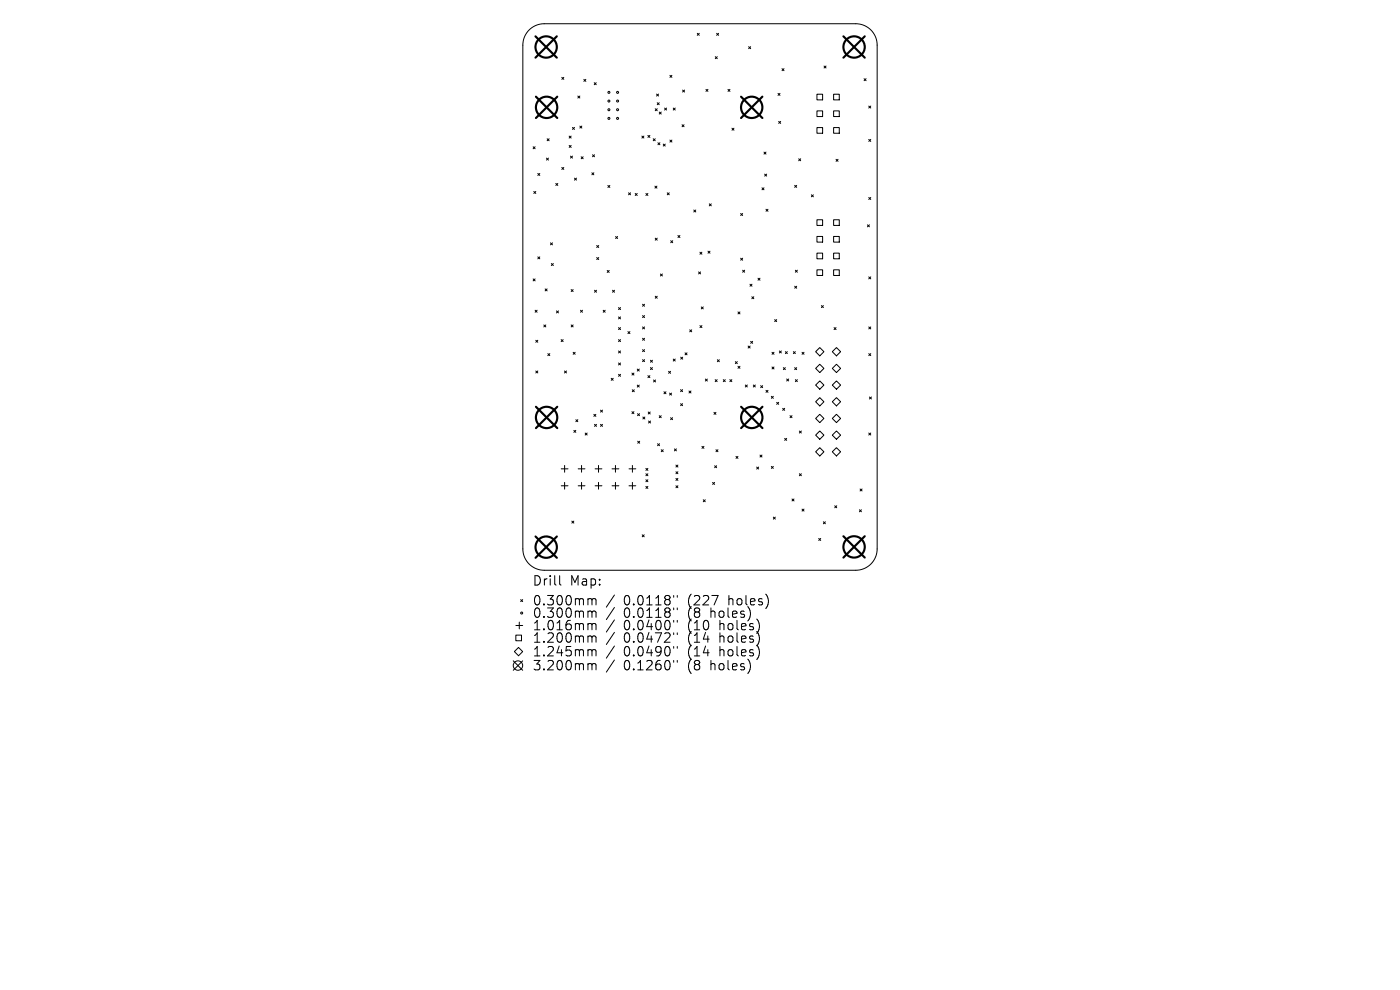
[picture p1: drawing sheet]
<svg xmlns="http://www.w3.org/2000/svg" width="297mm" height="210mm" viewBox="0 0 297 210" stroke-linecap="round" stroke-linejoin="round" font-family="sans-serif">
<defs><g id="words">
<g font-size="2.8">
<text x="112.9" y="124.5">Drill</text>
<text x="120.9" y="124.5">Map:</text>
<text x="112.9" y="128.7">0.300mm</text>
<text x="112.9" y="131.3">0.300mm</text>
<text x="132.3" y="128.7">0.0118&quot;</text>
<text x="132.3" y="131.3">0.0118&quot;</text>
<text x="146.1" y="128.7">(227</text>
<text x="146.1" y="131.3">(8</text>
<text x="151" y="131.3">holes)</text>
<text x="154.8" y="128.7">holes)</text>
<text x="112.9" y="134">1.016mm</text>
<text x="112.9" y="136.6">1.200mm</text>
<text x="132.3" y="134">0.0400&quot;</text>
<text x="132.3" y="136.6">0.0472&quot;</text>
<text x="146.1" y="134">(10</text>
<text x="146.1" y="136.6">(14</text>
<text x="152.9" y="134">holes)</text>
<text x="152.9" y="136.6">holes)</text>
<text x="112.9" y="139.5">1.245mm</text>
<text x="112.9" y="142.5">3.200mm</text>
<text x="132.3" y="139.5">0.0490&quot;</text>
<text x="132.3" y="142.5">0.1260&quot;</text>
<text x="146.1" y="139.5">(14</text>
<text x="146.1" y="142.5">(8</text>
<text x="151" y="142.5">holes)</text>
<text x="152.9" y="139.5">holes)</text>
</g>
</g></defs>
<g fill="none" stroke="#000" stroke-width=".21">
<path d="M112.2 6.4a4.5 4.5 0 0 1 3.2-1.4h66.2a4.5 4.5 0 0 1 4.5 4.6v106.8a4.5 4.5 0 0 1-4.5 4.6h-66.2a4.5 4.5 0 0 1-4.5-4.6v-106.8a4.5 4.5 0 0 1 1.3-3.2zM119.2 16.4l.4 .4M119.6 16.4l-.4 .4M123.9 16.8l.4 .5M124.3 16.8l-.4 .5M126.1 17.5l.4 .5M126.5 17.5l-.4 .5M139.3 19.9l.4 .5M139.7 19.9l-.4 .5M142.1 16l.4 .4M142.5 16l-.4 .4M144.8 19.1l.4 .4"/>
<path d="M145.2 19.1l-.4 .4M147.9 7.1l.4 .4M148.3 7.1l-.4 .4M149.8 19l.4 .4M150.2 19l-.4 .4M151.7 12l.5 .4M152 7.1l.5 .4M152.2 12l-.5 .4M152.5 7.1l-.5 .4M154.4 19l.5 .4M154.9 19l-.5 .4M158.8 9.9l.4 .4"/>
<path d="M159.2 9.9l-.4 .4M165.1 19.8l.4 .4M165.5 19.8l-.4 .4M165.9 14.6l.4 .4M166.3 14.6l-.4 .4M173.3 20h1.2v1.2h-1.2zM174.8 14l.4 .4M175.2 14l-.4 .4M176.8 20h1.2v1.2h-1.2zM183.3 16.7l.4 .4M183.7 16.7l-.4 .4M113.1 31.1l.4 .5"/>
<path d="M113.5 31.1l-.4 .5M114.1 36.8l.4 .4M114.5 36.8l-.4 .4M115.9 33.5l.5 .5M116.1 29.4l.4 .5M116.4 33.5l-.5 .5M116.5 29.4l-.4 .5M117.9 38.9l.4 .4M118.3 38.9l-.4 .4M119.2 35.5l.4 .4M119.6 35.5l-.4 .4M120.7 28.9l.5 .4"/>
<path d="M120.7 30.8l.5 .5M121 33.1l.5 .4M121.2 28.9l-.5 .4M121.2 30.8l-.5 .5M121.5 33.1l-.5 .4M121.5 27l.4 .5M121.9 27l-.4 .5M121.9 37.8l.4 .4M122.3 37.8l-.4 .4M122.6 20.4l.4 .4M123 20.4l-.4 .4M123 26.7l.4 .5"/>
<path d="M123.3 33.3l.4 .4M123.4 26.7l-.4 .5M123.7 33.3l-.4 .4M125.6 36.7l.4 .4M125.7 32.8l.4 .5M126 36.7l-.4 .4M126.1 32.8l-.4 .5M129 39.3l.4 .5M129.4 39.3l-.4 .5M136.2 28.9l.4 .4M136.6 28.9l-.4 .4M137.4 28.7l.5 .5"/>
<path d="M137.9 28.7l-.5 .5M138.6 29.4l.4 .5M138.9 39.5l.5 .4M139 29.4l-.4 .5M139 23.1l.4 .4M139.4 39.5l-.5 .4M139.4 23.1l-.4 .4M139.4 21.8l.5 .4M139.6 30.3l.4 .4M139.9 21.8l-.5 .4M139.9 23.8l.4 .4M140 30.3l-.4 .4"/>
<path d="M140.3 23.8l-.4 .4M140.7 30.6l.4 .4M141 22.9l.4 .4M141.1 30.6l-.4 .4M141.4 22.9l-.4 .4M142.1 29.7l.4 .4M142.5 29.7l-.4 .4M142.8 22.9l.5 .4M143.3 22.9l-.5 .4M144.7 26.5l.4 .4M145.1 26.5l-.4 .4M155.3 27.2l.4 .4"/>
<path d="M155.7 27.2l-.4 .4M161.7 39.8l.4 .5M162.1 39.8l-.4 .5M162.1 32.3l.4 .4M162.2 36.9l.4 .5M162.5 32.3l-.4 .4M162.6 36.9l-.4 .5M165.2 25.8l.4 .4M165.6 25.8l-.4 .4M168.6 39.3l.4 .4M169 39.3l-.4 .4M169.4 33.7l.5 .4"/>
<path d="M169.9 33.7l-.5 .4M173.3 23.5h1.2v1.2h-1.2zM173.3 27.1h1.2v1.2h-1.2zM176.8 23.5h1.2v1.2h-1.2zM176.8 27.1h1.2v1.2h-1.2zM177.4 33.8l.4 .4M177.8 33.8l-.4 .4M184.3 22.5l.4 .4M184.3 29.6l.4 .4M184.7 22.5l-.4 .4M184.7 29.6l-.4 .4M113.1 59.2l.4 .4"/>
<path d="M113.2 40.6l.5 .4M113.5 59.2l-.4 .4M113.7 40.6l-.5 .4M114.1 54.5l.4 .4M114.5 54.5l-.4 .4M116.8 51.5l.4 .4M117 55.9l.4 .4M117.2 51.5l-.4 .4M117.4 55.9l-.4 .4M126.6 52.1l.4 .4M126.6 54.6l.4 .5M127 52.1l-.4 .4"/>
<path d="M127 54.6l-.4 .5M128.8 57.4l.4 .4M129.2 57.4l-.4 .4M130.6 50.2l.4 .4M131 50.2l-.4 .4M133.3 40.9l.5 .4M133.8 40.9l-.5 .4M134.8 41l.4 .5M135.2 41l-.4 .5M137 41l.4 .5M137.4 41l-.4 .5M139 50.5l.4 .5"/>
<path d="M139.4 50.5l-.4 .5M140.1 58.1l.4 .4M140.5 58.1l-.4 .4M141.6 40.9l.4 .4M142 40.9l-.4 .4M142.3 51.1l.4 .4M142.7 51.1l-.4 .4M143.8 50l.4 .4M144.2 50l-.4 .4M147.2 44.5l.4 .5M147.6 44.5l-.4 .5M148.2 57.7l.4 .4"/>
<path d="M148.5 53.5l.4 .4M148.6 57.7l-.4 .4M148.9 53.5l-.4 .4M150.2 53.3l.4 .4M150.5 43.2l.4 .5M150.6 53.3l-.4 .4M150.9 43.2l-.4 .5M157.1 45.3l.4 .4M157.1 54.8l.4 .4M157.5 45.3l-.4 .4M157.5 54.8l-.4 .4M157.5 57.3l.5 .4"/>
<path d="M158 57.3l-.5 .4M160.8 59l.4 .4M161.2 59l-.4 .4M162.5 44.4l.4 .4M162.9 44.4l-.4 .4M168.7 57.3l.5 .4M169.2 57.3l-.5 .4M172.1 41.3l.5 .4M172.6 41.3l-.5 .4M173.3 46.6h1.2v1.2h-1.2zM173.3 50.2h1.2v1.2h-1.2zM173.3 53.7h1.2v1.2h-1.2z"/>
<path d="M173.3 57.2h1.2v1.2h-1.2zM176.8 46.6h1.2v1.2h-1.2zM176.8 50.2h1.2v1.2h-1.2zM176.8 53.7h1.2v1.2h-1.2zM176.8 57.2h1.2v1.2h-1.2zM184 47.7l.4 .4M184.3 41.9l.4 .4M184.3 58.7l.4 .5M184.4 47.7l-.4 .4M184.7 41.9l-.4 .4M184.7 58.7l-.4 .5M113.5 65.8l.4 .4"/>
<path d="M113.7 72.2l.4 .4M113.7 78.7l.4 .4M113.9 65.8l-.4 .4M114.1 72.2l-.4 .4M114.1 78.7l-.4 .4M115.4 68.9l.4 .5M115.6 61.3l.5 .4M115.8 68.9l-.4 .5M116.1 61.3l-.5 .4M116.2 75l.4 .4M116.6 75l-.4 .4M118.1 66l.4 .4"/>
<path d="M118.5 66l-.4 .4M119 72l.5 .5M119.5 72l-.5 .5M119.8 78.7l.4 .4M120.2 78.7l-.4 .4M121.2 61.4l.4 .4M121.2 68.9l.4 .5M121.6 61.4l-.4 .4M121.6 68.9l-.4 .5M121.6 74.7l.4 .5M122 74.7l-.4 .5M123.2 65.8l.4 .4"/>
<path d="M123.6 65.8l-.4 .4M126.1 61.6l.4 .4M126.5 61.6l-.4 .4M128 65.8l.4 .4M128.4 65.8l-.4 .4M129.9 61.6l.5 .4M130.4 61.6l-.5 .4M131.2 65.2l.4 .5M131.2 67.2l.4 .5M131.2 69.5l.4 .4M131.2 72l.4 .5M131.2 74.4l.4 .5"/>
<path d="M131.2 77l.4 .4M131.2 79.4l.4 .4M131.6 67.2l-.4 .5M131.6 65.2l-.4 .5M131.6 69.5l-.4 .4M131.6 72l-.4 .5M131.6 74.4l-.4 .5M131.6 77l-.4 .4M131.6 79.4l-.4 .4M133.2 70.3l.4 .5M133.6 70.3l-.4 .5M134.1 79.1l.4 .5"/>
<path d="M134.5 79.1l-.4 .5M135.2 78.3l.4 .4M135.6 78.3l-.4 .4M136.3 71.8l.4 .4M136.3 74.2l.4 .4M136.3 64.5l.4 .5M136.3 66.9l.4 .5M136.3 69.4l.4 .4M136.3 76.3l.4 .4M136.7 66.9l-.4 .5M136.7 69.4l-.4 .4M136.7 64.5l-.4 .5"/>
<path d="M136.7 71.8l-.4 .4M136.7 74.2l-.4 .4M136.7 76.3l-.4 .4M137.4 79.7l.5 .4M137.9 79.7l-.5 .4M138 78l.4 .4M138 76.4l.4 .4M138.4 78l-.4 .4M138.4 76.4l-.4 .4M139 62.8l.4 .5M139.4 62.8l-.4 .5M141.8 78.8l.5 .4"/>
<path d="M142.3 78.8l-.5 .4M142.8 76.2l.5 .4M143.3 76.2l-.5 .4M144.4 75.8l.4 .4M144.8 75.8l-.4 .4M145.3 74.8l.5 .5M145.8 74.8l-.5 .5M146.3 70l.4 .4M146.7 70l-.4 .4M148.5 69.1l.4 .4M148.8 65.1l.4 .4M148.9 69.1l-.4 .4"/>
<path d="M149.2 65.1l-.4 .4M152.2 76.3l.4 .4M152.6 76.3l-.4 .4M156 76.7l.4 .4M156.4 76.7l-.4 .4M156.6 66.2l.4 .4M156.6 77.7l.4 .4M157 66.2l-.4 .4M157 77.7l-.4 .4M158.7 73.4l.4 .4M159.1 60.3l.4 .4M159.1 73.4l-.4 .4"/>
<path d="M159.2 72.4l.5 .4M159.5 62.9l.4 .5M159.5 60.3l-.4 .4M159.7 72.4l-.5 .4M159.9 62.9l-.4 .5M163.8 74.7l.4 .5M163.8 77.8l.4 .5M164.2 74.7l-.4 .5M164.2 77.8l-.4 .5M164.3 67.8l.5 .4M164.8 67.8l-.5 .4M165.3 74.4l.5 .5"/>
<path d="M165.8 74.4l-.5 .5M166.2 78l.4 .4M166.6 74.6l.4 .4M166.6 78l-.4 .4M167 74.6l-.4 .4M168.3 74.6l.4 .4M168.6 78l.4 .4M168.6 60.7l.4 .4M168.7 74.6l-.4 .4M169 60.7l-.4 .4M169 78l-.4 .4M170.1 74.7l.5 .5"/>
<path d="M170.6 74.7l-.5 .5M173 74.6l.9-.9 .9 .9-.9 .9zM173 78.1l.9-.8 .9 .8-.9 .9zM174.3 64.8l.4 .4M174.7 64.8l-.4 .4M176.6 74.6l.8-.9 .9 .9-.9 .9zM176.6 78.1l.8-.8 .9 .8-.9 .9zM176.9 69.5l.5 .4M177.4 69.5l-.5 .4M184.3 75l.4 .4M184.3 69.4l.4 .4M184.7 69.4l-.4 .4"/>
<path d="M184.7 75l-.4 .4M119.1 99.5h1.4M119.8 98.7v1.5M121.7 91.3l.5 .4M122.2 91.3l-.5 .4M122.2 89l.4 .5M122.6 89l-.4 .5M122.7 99.5h1.4M123.4 98.7v1.5M124.1 91.9l.5 .4M124.6 91.9l-.5 .4M126 87.9l.4 .4"/>
<path d="M126.1 90l.4 .4M126.3 99.5h1.4M126.4 87.9l-.4 .4M126.5 90l-.4 .4M127 98.7v1.5M127.4 87l.4 .4M127.4 90l.4 .4M127.8 87l-.4 .4M127.8 90l-.4 .4M129.7 80.3l.4 .4M129.8 99.5h1.5M130.1 80.3l-.4 .4"/>
<path d="M130.6 98.7v1.5M133.4 99.5h1.5M134.1 87.3l.4 .5M134.1 82.7l.5 .4M134.2 98.7v1.5M134.5 87.3l-.4 .5M134.6 82.7l-.5 .4M135.2 81.7l.4 .4M135.3 87.8l.4 .4M135.3 93.6l.4 .4M135.6 81.7l-.4 .4M135.7 87.8l-.4 .4"/>
<path d="M135.7 93.6l-.4 .4M136.4 88.5l.4 .4M136.8 88.5l-.4 .4M137 99.4l.4 .4M137.4 99.4l-.4 .4M137.5 87.4l.4 .4M137.6 89.3l.4 .4M137.9 87.4l-.4 .4M138 89.3l-.4 .4M138.6 80.6l.5 .4M139.1 80.6l-.5 .4M139.5 94.1l.4 .4"/>
<path d="M139.9 88.2l.4 .4M139.9 94.1l-.4 .4M140.3 88.2l-.4 .4M140.3 95.4l.4 .4M140.7 95.4l-.4 .4M140.9 83.1l.4 .4M141.3 83.1l-.4 .4M142 83.4l.5 .4M142.3 88.6l.4 .4M142.5 83.4l-.5 .4M142.7 88.6l-.4 .4M143.1 95.2l.4 .4"/>
<path d="M143.4 98.7l.4 .4M143.5 95.2l-.4 .4M143.8 98.7l-.4 .4M144.4 82.7l.4 .4M144.4 85.6l.4 .5M144.8 82.7l-.4 .4M144.8 85.6l-.4 .5M146.2 82.9l.4 .5M146.6 82.9l-.4 .5M148.9 94.7l.4 .4M149.3 94.7l-.4 .4M149.6 80.4l.5 .4"/>
<path d="M150.1 80.4l-.5 .4M151.5 87.5l.4 .4M151.6 98.8l.4 .4M151.7 80.5l.4 .5M151.9 87.5l-.4 .4M151.9 95.4l.4 .4M152 98.8l-.4 .4M152.1 80.5l-.4 .5M152.3 95.4l-.4 .4M153.4 80.5l.5 .5M153.9 80.5l-.5 .5M154.8 80.5l.5 .5"/>
<path d="M155.3 80.5l-.5 .5M156.1 96.8l.5 .4M156.6 96.8l-.5 .4M158.1 81.7l.4 .4M158.5 81.7l-.4 .4M159.8 81.7l.4 .4M160.2 81.7l-.4 .4M160.5 99.1l.4 .4M160.9 99.1l-.4 .4M161.2 96.5l.5 .5M161.4 81.8l.4 .4M161.7 96.5l-.5 .5"/>
<path d="M161.8 81.8l-.4 .4M162.5 82.8l.4 .4M162.9 82.8l-.4 .4M163.6 98.9l.5 .5M163.6 84.1l.5 .4M164.1 84.1l-.5 .4M164.1 98.9l-.5 .5M164.8 85.3l.4 .5M165.2 85.3l-.4 .5M166 86.6l.5 .4M166.5 86.6l-.5 .4M166.5 93l.4 .4"/>
<path d="M166.9 93l-.4 .4M166.9 80.4l.4 .4M167.3 80.4l-.4 .4M167.6 88.2l.4 .4M168 88.2l-.4 .4M168.7 80.5l.5 .5M169.2 80.5l-.5 .5M169.6 91.4l.4 .5M170 91.4l-.4 .5M173 85.2l.9-.9 .9 .9-.9 .9zM173 88.8l.9-.9 .9 .9-.9 .8zM173 92.3l.9-.9 .9 .9-.9 .9z"/>
<path d="M173 95.8l.9-.8 .9 .8-.9 .9zM173.9 80.8l.9 .9-.9 .9-.9-.9zM176.6 81.7l.8-.9 .9 .9-.9 .9zM176.6 85.2l.8-.9 .9 .9-.9 .9zM176.6 88.8l.8-.9 .9 .9-.9 .8zM176.6 92.3l.8-.9 .9 .9-.9 .9zM176.6 95.8l.8-.8 .9 .8-.9 .9zM184.3 91.9l.4 .4M184.4 84.2l.5 .4M184.7 91.9l-.4 .4M184.9 84.2l-.5 .4M119.1 103h1.4"/>
<path d="M119.8 102.3v1.5M121.3 110.5l.4 .5M121.7 110.5l-.4 .5M122.7 103h1.4M123.4 102.3v1.5M126.3 103h1.4M127 102.3v1.5M129.8 103h1.5M130.6 102.3v1.5M133.4 103h1.5M134.2 102.3v1.5M136.2 113.4l.5 .5"/>
<path d="M136.7 113.4l-.5 .5M137 100.5l.4 .4M137 101.8l.4 .4M137 103.2l.4 .4M137.4 100.5l-.4 .4M137.4 101.8l-.4 .4M137.4 103.2l-.4 .4M143.4 100.1l.4 .4M143.4 101.5l.4 .4M143.4 103l.4 .5M143.8 100.1l-.4 .4M143.8 101.5l-.4 .4"/>
<path d="M143.8 103l-.4 .5M149.2 106l.4 .4M149.6 106l-.4 .4M151.2 102.3l.4 .5M151.6 102.3l-.4 .5M164.1 109.7l.4 .4M164.5 109.7l-.4 .4M168 105.8l.4 .5M168.4 105.8l-.4 .5M169.6 100.5l.4 .4M170 100.5l-.4 .4M170.1 108l.5 .4"/>
<path d="M170.6 108l-.5 .4M173.7 114.2l.4 .4M174.1 114.2l-.4 .4M174.7 110.7l.4 .4M175.1 110.7l-.4 .4M177.1 107.3l.4 .4M177.5 107.3l-.4 .4M182.3 108.1l.4 .5M182.5 103.7l.4 .4M182.7 108.1l-.4 .5M182.9 103.7l-.4 .4M109.4 134.7h1.2v1.2h-1.2z"/>
<path d="M109.4 132.7h1.5M110 137.3l.9 .9-.9 .9-.9-.9zM110.2 132v1.4M110.5 127.2l.4 .4M110.9 127.2l-.4 .4M118.7 122.1v1.7l.3 .3M125 127h.3l.3 .3M125 129.6h.3l.3 .3M125 132.3l.5 .1 .1 .2M125 134.9l.5 .1 .1 .2M125 137.8l.5 .1 .1 .2M125.6 127.3l.3-.3 .4 .1 .1 1.2"/>
<path d="M125.6 127.3v1M125.6 129.9v1.1M125.6 132.6v1M125.6 135.2v1M125.6 138.1v1M125.6 129.9l.3-.3 .4 .1 .1 1.3M125.6 132.6l.3-.3 .4 .1 .1 1.2M125.6 135.2l.3-.3 .4 .1 .1 1.2M125.6 138.1l.3-.3 .4 .1 .1 1.2M130.3 126.2l-1.7 2.6M130.3 128.9l-1.7 2.5M130.3 131.5l-1.7 2.6"/>
<path d="M130.3 134.1l-1.7 2.6M130.3 137l-1.7 2.6M142.9 126.3v.4M142.9 129v.3M142.9 131.6v.4M142.9 134.2v.4M142.9 137.1v.4M143.7 126.3v.4M143.7 129v.3M143.7 131.6v.4M143.7 134.2v.4M143.7 137.1v.4"/>
<path d="M108.9 140.2l2 2M110.9 140.2l-2 2M125 140.8h.3l.3 .3M125.6 141.1v1M125.6 141.1l.3-.3 .4 .1 .1 1.2M130.3 140l-1.7 2.6M142.9 140.1v.4M143.7 140.1v.4"/>
<circle cx="129.2" cy="19.6" r=".21"/>
<circle cx="131" cy="19.6" r=".21"/>
<circle cx="129.2" cy="21.4" r=".21"/>
<circle cx="129.2" cy="25.1" r=".21"/>
<circle cx="129.2" cy="23.3" r=".21"/>
<circle cx="131" cy="21.4" r=".21"/>
<circle cx="131" cy="25.1" r=".21"/>
<circle cx="131" cy="23.3" r=".21"/>
<circle cx="110.7" cy="130" r=".21"/>
<circle cx="109.9" cy="141.2" r="1"/>
</g>
<g fill="none" stroke="#000" stroke-width=".45">
<path d="M113.6 7.7l4.5 4.5M118.1 7.7l-4.5 4.5M178.9 7.7l4.6 4.5M183.5 7.7l-4.6 4.5M113.7 20.5l4.5 4.5M118.2 20.5l-4.5 4.5M157.2 20.5l4.5 4.5M161.7 20.5l-4.5 4.5M113.7 86.3l4.5 4.5M118.2 86.3l-4.5 4.5M157.2 86.3l4.6 4.5M161.8 86.3l-4.6 4.5"/>
<path d="M113.6 113.8l4.5 4.5M118.1 113.8l-4.5 4.5M178.9 113.7l4.6 4.6M183.5 113.7l-4.6 4.6"/>
<circle cx="115.9" cy="10" r="2.26"/>
<circle cx="181.2" cy="10" r="2.26"/>
<circle cx="116" cy="22.8" r="2.26"/>
<circle cx="159.5" cy="22.8" r="2.26"/>
<circle cx="116" cy="88.6" r="2.26"/>
<circle cx="159.5" cy="88.6" r="2.26"/>
<circle cx="115.9" cy="116.1" r="2.26"/>
<circle cx="181.2" cy="116" r="2.26"/>
</g>
<use href="#words"/>
</svg>
